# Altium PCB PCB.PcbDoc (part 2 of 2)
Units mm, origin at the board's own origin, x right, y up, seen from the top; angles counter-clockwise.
Board outline 85 x 56 mm, 4 copper layers (TOP, GND, SIG, BOTTOM), stack 1.586 mm thick; 75 components, 165 nets, 429 pads, 246 vias.

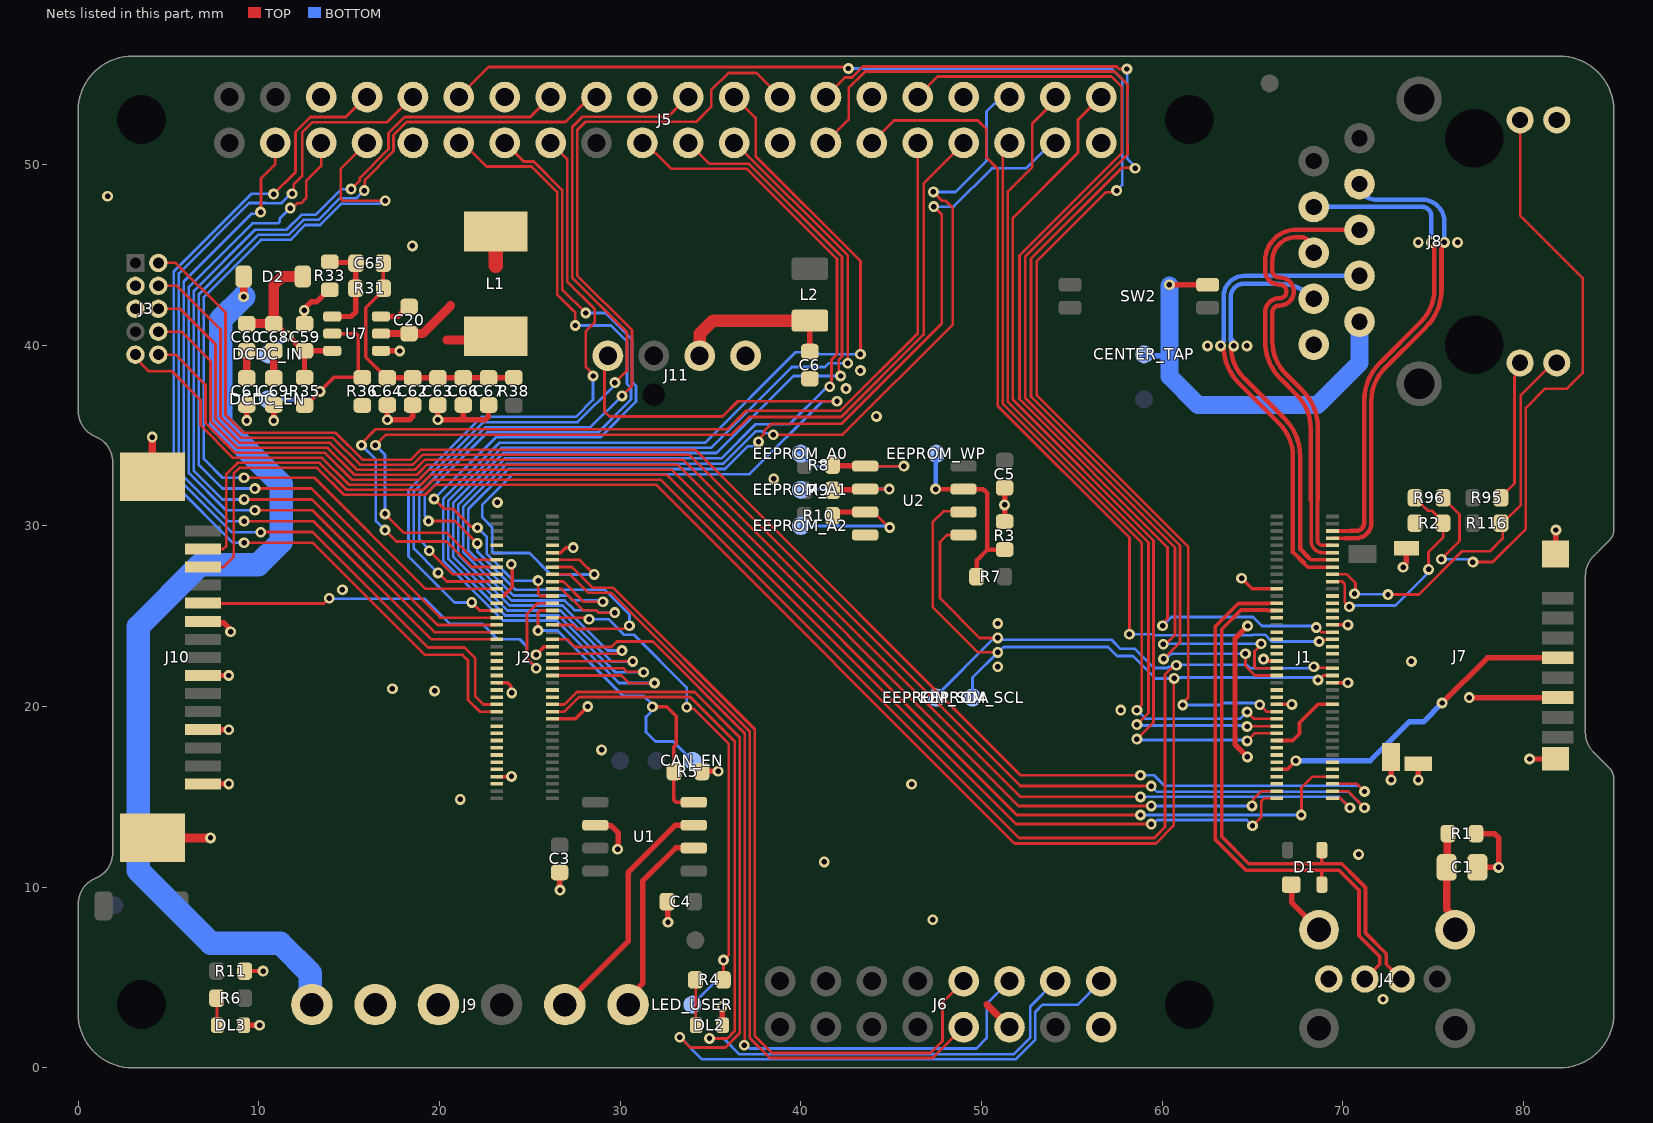
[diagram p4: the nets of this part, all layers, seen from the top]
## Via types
v1: diameter 0.6, hole 0.3, TOP to BOTTOM, tented both sides, 246 vias

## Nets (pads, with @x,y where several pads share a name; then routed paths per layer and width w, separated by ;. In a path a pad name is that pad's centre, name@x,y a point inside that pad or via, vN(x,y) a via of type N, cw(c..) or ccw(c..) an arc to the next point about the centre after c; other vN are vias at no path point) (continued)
ETH_B_N: J1.7 J8.8 | length 26.6
  TOP w0.2: J1.7@69.433,29.32 70.139,29.32 70.14,29.319
  TOP w0.25: 70.14,29.319 70.719,29.319 ccw(c70.719,30.187) 71.587,30.187 71.587,36.935 cw(c74.127,36.935) 72.331,38.731 74.603,41.003 ccw(c72.523,43.081) 75.463,43.063 75.463,45.322 cw(c75.743,45.322) 75.545,45.52 v1@75.56,45.534 ; v1@75.56,45.535 ccw(c75.398,45.696) v1(75.627,45.696)
  BOTTOM w0.25: J8.8@70.925,48.925 ccw(c71.79,48.925) 71.79,48.06 74.394,48.06 cw(c74.394,46.827) 75.627,46.827 v1(75.627,45.696)
ETH_B_P: J1.5 J8.7 | length 27.2
  TOP w0.2: J1.5@69.433,29.72 70.43,29.72
  TOP w0.25: 70.43,29.719 70.719,29.719 ccw(c70.719,30.187) 71.187,30.187 71.187,36.935 cw(c74.127,36.935) 72.048,39.014 74.32,41.285 ccw(c72.523,43.081) 75.063,43.065 75.063,45.322 ccw(c74.784,45.322) 74.982,45.52 v1@74.967,45.534 ; v1(74.9,45.696) ccw(c75.129,45.696) v1@74.967,45.535
  BOTTOM w0.25: J8.7@68.385,47.655 68.385,47.66 74.394,47.66 cw(c74.394,47.154) 74.9,47.154 v1(74.9,45.696)
ETH_C_N: J1.11 J8.6 | length 25.5
  TOP w0.2: 68.222,31.425 68.247,31.4 68.247,29.168 ccw(c68.894,29.168) 68.894,28.52 J1.11@69.433,28.52
  TOP w0.25: 68.222,31.425 68.222,35.426 ccw(c65.682,35.426) 67.478,37.222 66.56,38.14 cw(c68.637,40.217) 65.7,40.217 65.7,40.677 65.7,41.821 cw(c66.479,41.821) 66.479,42.6 66.504,42.6 ccw(c66.504,42.979) 66.504,43.358 66.479,43.358 cw(c66.479,44.137) 65.7,44.137 65.7,44.462 65.7,44.672 cw(c67.415,44.676) 67.536,46.387 67.55,46.386 ccw(c67.568,46.635) 67.567,46.385 J8.6@70.925,46.385
ETH_C_P: J1.9 J8.5 | length 22.2
  TOP w0.2: 68.622,31.425 68.597,31.4 68.597,29.218 ccw(c68.894,29.218) 68.894,28.92 J1.9@69.433,28.92
  TOP w0.25: J8.5@68.385,45.115 ccw(c67.448,45.115) 67.851,45.961 ccw(c67.744,45.735) 67.745,45.985 67.565,45.985 cw(c67.568,46.635) 67.519,45.987 ccw(c67.415,44.676) 66.1,44.675 66.1,44.462 66.1,44.137 ccw(c66.479,44.137) 66.479,43.758 66.504,43.758 cw(c66.504,42.979) 66.504,42.2 66.479,42.2 ccw(c66.479,41.821) 66.1,41.821 66.1,40.677 66.1,40.218 ccw(c68.64,40.218) 66.844,38.422 67.763,37.503 cw(c65.689,35.429) 68.622,35.429 68.622,31.425
ETH_D_N: J1.15 J8.4 | length 26.4
  TOP w0.2: 67.857,27.936 68.073,27.72 J1.15@69.433,27.72
  TOP w0.25: v1@63.4,39.961 ccw(c66.337,39.961) 64.26,37.884 66.496,35.648 cw(c64.7,33.852) 67.24,33.852 67.24,28.553 67.857,27.936
  BOTTOM w0.25: v1@63.4,39.962 v1(63.237,39.962) 63.237,40.057 63.4,40.22 63.4,42.7 cw(c64.545,42.7) 64.545,43.845 J8.4@70.925,43.845
ETH_D_P: J1.13 J8.3 | length 23.1
  TOP w0.2: 68.14,28.219 68.239,28.12 J1.13@69.433,28.12
  TOP w0.25: v1@63.8,39.962 ccw(c66.34,39.962) 64.544,38.166 66.781,35.929 cw(c64.708,33.855) 67.64,33.855 67.64,28.719 68.14,28.219
  BOTTOM w0.25: J8.3@68.385,42.575 68.304,42.656 ccw(c66.508,40.86) 66.508,43.4 64.5,43.4 ccw(c64.5,42.7) 63.8,42.7 63.8,40.362 ; 63.8,40.362 63.8,40.22 v1@63.897,40.124 ; 63.8,40.362 63.897,40.266 v1@63.897,40.124 ; v1@63.897,40.124 63.897,40.029 v1(63.964,39.962) 63.964,40.057 v1@63.897,40.124
ETH_LED1: J1.17 J8.14 R116.1 | length 22.7
  TOP w0.15: J1.17@69.433,27.32 70.222,27.32 70.699,26.844 70.699,26.295 v1(70.648,26.244) ; v1(72.5,26.2) 74.206,26.2 76.604,28.598 78.148,28.598 78.85,29.3 R116.1@78.85,30.15 ; R116.1@78.85,30.152 79.856,31.158 79.856,37.256 81.625,39.025 J8.14@81.845,39.025
  BOTTOM w0.15: v1(70.648,26.244) 70.67,26.222 72.478,26.222 v1(72.5,26.2)
ETH_LED2: J1.19 R2.1 R96.2 | length 12.5
  TOP w0.15: J1.19@69.433,26.92 69.98,26.92 70.1,26.8 70.1,25.792 v1(70.368,25.524) ; R96.2@74,31.55 74,31.548 74.393,31.155 74.395,31.155 74.709,30.841 74.934,30.841 75.55,30.225 R2.1@75.55,30.15 ; v1(74.746,27.595) 74.746,28.559 75.558,29.371 R2.1@75.558,30.142
  BOTTOM w0.15: v1(70.368,25.524) 70.442,25.598 72.908,25.598 74.605,27.295 74.605,27.332 74.746,27.474 v1(74.746,27.595)
GND: C1.1 C3.2 C4.2 C5.2 C6.1 C59.2 C61.1 C62.1 C63.1 C64.2 C66.1 C67.1 C69.1 DL2.C DL3.C J1.22 J1.31 J1.42 J1.47 J1.54 J2.24 J2.33 J2.44 J2.57 J2.70 J3.3 J3.5 J4.4 J5.6 J5.9 J5.14 J5.20 J5.25 J5.30 J5.34 J5.39 J6.15 J7.6 J7.CD2 J7.SH1 J7.SH2 J7.SH3 J7.SH4 J8.1 J8.12 J9.2 J9.3 J10.1 J10.4 J10.7 J10.10 J10.FIX J11.4 R1.1 R2.2 R3.1 R5.1 R11.1 R33.1 R36.2 U1.2 U2.4 U7.4 | length 72
  TOP w0.2: R11.1@9.212,5.36 v1(10.237,5.36) ; J2.33@23.173,21.32 23.772,21.32 23.943,21.149 23.943,20.815 v1(24,20.758) ; J2.57@23.173,26.12 23.544,26.12 24.023,26.599 24.023,27.82 v1(23.967,27.876) ; v1(25.344,22.871) 25.792,23.32 J2.44@26.253,23.32 ; J2.24@26.253,19.32 27.524,19.32 v1(28.208,20.005) ; J2.70@26.253,28.52 26.703,28.52 26.982,28.799 v1(27.4,28.799) ; v1(64.398,27.104) 64.981,26.52 J1.22@66.353,26.52 ; v1(65.612,22.625) 65.72,22.625 65.826,22.52 J1.42@66.353,22.52 ; J1.54@66.353,20.12 v1(67.179,20.12) ; J1.47@69.433,21.32 v1(70.279,21.32) ; J1.31@69.433,24.52 v1(70.279,24.52)
  TOP w0.3: J10.1@6.9,15.72 v1(8.334,15.72) ; J10.4@6.9,18.72 v1(8.334,18.72) ; J10.7@6.9,21.72 v1(8.334,21.72) ; J10.10@6.9,24.72 6.972,24.648 8.05,24.648 8.378,24.32 8.378,24.202 v1(8.436,24.145) ; DL3.C@9.162,2.36 v1(10.04,2.36) ; v1(9.328,35.83) C61.1@9.328,36.694 ; v1(10.828,35.83) C69.1@10.828,36.694 ; C59.2@12.528,41.194 12.522,41.2 12.522,41.926 v1(12.515,41.932) 12.573,41.99 12.573,42.079 12.896,42.402 13.186,42.402 13.853,43.069 R33.1@13.928,43.069 ; U7.4@16.762,39.694 16.767,39.689 17.792,39.689 v1(17.796,39.684) ; C64.2@17.112,36.694 v1(17.112,35.873) 18.331,35.873 18.512,36.054 C62.1@18.512,36.694 ; C63.1@19.912,36.694 v1(19.912,35.873) 21.321,35.873 ; C66.1@21.321,36.685 21.321,35.873 ; C67.1@22.712,36.694 22.712,36.054 22.531,35.873 21.321,35.873 ; C3.2@26.646,10.815 26.658,10.803 26.658,9.85 v1(26.67,9.838) ; U1.2@28.625,13.435 28.646,13.414 29.5,13.414 29.885,13.029 29.885,12.133 v1(29.857,12.104) ; C4.2@32.6,9.2 32.624,9.176 32.624,8.082 v1(32.649,8.057) ; R5.1@34.525,16.4 34.537,16.412 35.41,16.412 v1(35.422,16.423) ; v1(35.649,3.396) 35.656,3.389 35.656,2.367 DL2.C@35.662,2.36 ; R3.1@51.28,30.241 v1(51.28,31.166) C5.2@51.28,32.116 ; v1(64.722,17.215) 64.031,17.905 64.031,23.766 64.725,24.46 v1(64.728,24.46) ; v1(72.675,15.939) J7.CD2@72.675,17.197 ; v1(73.339,27.714) 73.339,27.795 73.502,27.957 73.502,28.751 J7.SH3@73.525,28.774 ; v1(74.175,15.939) J7.SH4@74.175,16.824 ; v1(77,20.5) J7.6@81.899,20.499 ; R1.1@77.371,12.965 78.396,12.965 78.495,12.866 78.621,12.74 v1(78.621,11.1) C1.1@77.45,11.101 ; v1(80.339,17.099) J7.SH1@81.772,17.099 ; J7.SH2@81.772,28.449 81.798,28.475 v1(81.798,29.774)
  TOP w0.4: J10.FIX@4.1,32.71 v1(4.1,34.918)
  TOP w0.5: J10.FIX@4.1,12.73 v1(7.322,12.73)
  other v1: 72.225,3.8 47.3,8.2 41.3,11.4 70.877,11.818 21.148,14.863 28.971,17.602 57.706,19.806 19.731,20.868 17.392,20.985 50.9,22.2 73.8,22.5 50.9,24.6 14.621,26.464 23.2,31.299 38.5,32.6 44.18,36.066 42.5,37.6 43.3,38.6 62.51,39.962 64.691,39.962 18.5,45.5 74.173,45.696 76.354,45.696 1.626,48.244
GPIO0_1: J2.46 J6.12 | length 47.7
  TOP w0.15: J2.46@26.253,23.72 27.08,23.72 27.503,23.297 29.508,23.297 29.812,23.601 31.81,23.601 36.896,18.515 36.896,7.371 36.896,1.278 v1(36.87,1.252)
  BOTTOM w0.15: v1(36.87,1.252) 36.992,1.252 37.166,1.078 49.717,1.078 50.287,1.648 50.287,3.537 J6.12@51.55,4.8
GPIO2_1: J2.50 J5.11 | length 54.6
  TOP w0.15: v1(19.389,30.269) 20.853,30.269 v1(22.088,29.034) ; J5.11@21.07,51.23 21.27,51.23 22.6,49.9 25.1,49.9 26.51,48.49 26.51,42.809 27.512,41.807 v1(27.512,41.094) ; J2.50@26.253,24.52 27.378,24.52 27.6,24.298 28.708,24.298 28.711,24.301 30.212,24.301 30.389,24.478 v1(30.511,24.478)
  BOTTOM w0.15: v1(19.389,30.269) 19.389,30.382 19.189,30.582 19.189,31.723 22.651,35.185 28.795,35.185 30.602,36.992 30.602,37.636 30.372,37.866 30.372,40.204 29.482,41.094 v1(27.512,41.094) ; v1(22.088,29.034) 22.088,28.574 24.193,26.469 29.141,26.469 30.511,25.099 v1(30.511,24.478)
GPIO02_SDA: J2.45 J5.3 | length 41.9
  TOP w0.15: v1(9.18,30.266) 13.009,30.266 19.554,23.72 J2.45@23.173,23.72 ; v1(10.094,47.367) 10.122,47.395 10.122,49.241 10.91,50.029 J5.3@10.91,51.23
  BOTTOM w0.15: v1(9.18,30.266) 8.29,30.266 5.844,32.712 5.844,43.544 9.581,47.281 10.008,47.281 v1(10.094,47.367)
GPIO3_1: J2.52 LED_USER.X R4.2 | length 29.6
  TOP w0.15: J2.52@26.253,24.92 28.198,24.92 v1(28.281,24.837) ; v1(33.682,19.959) 33.758,19.882 34.048,19.882 36.012,17.918 36.012,6.257 v1(35.719,5.964) R4.2@35.719,4.877
  BOTTOM w0.15: v1(28.281,24.837) 29.353,24.837 30.214,23.976 30.761,23.976 33.682,21.055 v1(33.682,19.959) ; LED_USER.X@34,3.501 35.719,5.22 v1(35.719,5.964)
GPIO03_SCL: J2.47 J5.5 | length 43.1
  TOP w0.15: v1(9.78,30.866) 12.974,30.866 19.72,24.12 J2.47@23.173,24.12 ; v1(11.737,47.594) 11.858,47.594 12.117,47.853 12.326,47.853 12.62,48.147 12.62,49.082 13.45,49.912 J5.5@13.45,51.23
  BOTTOM w0.15: v1(9.78,30.866) 8.18,30.866 6.121,32.925 6.121,43.228 9.64,46.748 11.057,46.748 11.156,46.847 11.156,47.013 v1(11.737,47.594)
GPIO4_1: CAN_EN.X J2.54 R5.2 U1.8 | length 22.2
  TOP w0.15: v1(25.452,24.208) 25.452,25.232 25.54,25.32 J2.54@26.253,25.32
  TOP w0.2: v1(31.786,19.993) 32.581,19.993 33.111,19.462 33.111,17.92 32.975,17.784 R5.2@32.975,16.4 32.975,14.825 33.095,14.705 U1.8@34.075,14.705
  BOTTOM w0.15: v1(25.452,24.208) 26.539,24.208 30.146,20.6 31.3,20.6 31.786,20.114 v1(31.786,19.993) 31.7,19.907 31.7,19.7 31.429,19.429 31.429,18.583 31.95,18.062 32.938,18.062 CAN_EN.X@34,17
GPIO04_1WIRE: J2.59 J5.7 | length 46.7
  TOP w0.15: v1(9.18,32.666) 13.08,32.666 19.225,26.52 J2.59@23.173,26.52 ; J5.7@15.99,51.23 14.537,49.777 14.537,48.105 14.643,48 v1(17,48)
  BOTTOM w0.15: v1(9.18,32.666) 7.98,32.666 6.952,33.694 6.952,42.677 10.11,45.835 11.745,45.835 12.565,46.654 13.391,46.654 14.576,47.839 16.717,47.839 16.878,48 v1(17,48)
GPIO05: J1.35 J5.29 | length 49.8
  TOP w0.15: J5.29@43.93,51.23 45.146,52.446 49.793,52.446 50.269,51.969 50.269,50.395 50.9,49.764 50.9,36.647 58.187,29.36 v1(58.187,24.004) ; v1(68.685,23.6) 68.807,23.6 68.901,23.695 69.408,23.695 J1.35@69.433,23.72
  BOTTOM w0.15: v1(58.187,24.004) 59.508,24.004 59.561,23.951 65.008,23.951 65.038,23.982 65.684,23.982 66.065,23.6 v1(68.685,23.6)
GPIO5_1: J2.56 J10.11 | length 25.5
  TOP w0.15: J10.11@6.9,25.72 6.91,25.711 13.611,25.711 v1(13.9,26) ; v1(25.353,22.125) 25.353,22.152 24.842,22.664 24.842,25.131 25.43,25.72 J2.56@26.253,25.72
  BOTTOM w0.15: v1(13.9,26) 13.938,25.962 19.183,25.962 20.58,24.566 22.38,24.566 23.22,23.726 24.44,23.726 24.83,23.336 24.83,22.648 v1(25.353,22.125)
GPIO06: J2.65 J5.31 | length 56.3
  TOP w0.15: v1(15.68,34.466) 15.68,34.566 16.469,35.355 35.951,35.355 36.977,36.381 42.191,36.381 46.47,40.66 J5.31@46.47,51.23 ; v1(16.98,29.766) 17.61,29.136 20.377,29.136 21.793,27.72 J2.65@23.173,27.72
  BOTTOM w0.15: v1(15.68,34.466) 16.478,33.668 16.478,30.268 v1(16.98,29.766)
GPIO6_1: J2.58 J5.13 | length 41.5
  TOP w0.15: v1(19.699,31.491) 20.241,30.949 20.751,30.949 21.729,29.971 22.029,29.971 v1(22.1,29.9) ; J5.13@23.61,51.23 24.663,50.177 25.215,50.177 26.787,48.605 26.787,43.094 v1(28.098,41.784) ; v1(25.457,26.971) 25.457,26.243 25.58,26.12 J2.58@26.253,26.12
  BOTTOM w0.15: v1(19.699,31.491) 23.116,34.908 28.91,34.908 30.879,36.877 30.879,37.751 30.649,37.981 30.649,40.319 29.184,41.784 v1(28.098,41.784) ; v1(22.1,29.9) 22.617,29.383 22.617,28.437 24.083,26.971 v1(25.457,26.971)
GPIO07_SPI0_CE1_N: J2.63 J5.26 | length 51
  TOP w0.15: v1(19.428,28.629) 20.737,27.32 J2.63@23.173,27.32 ; v1(30.1,37.2) 30.649,37.749 30.649,40.835 27.618,43.866 27.618,51.902 28.087,52.372 34.213,52.372 35.036,53.194 35.036,54.12 35.987,55.071 37.549,55.071 J5.26@38.85,53.77
  BOTTOM w0.15: v1(19.428,28.629) 19.428,28.704 18.883,29.249 18.883,31.81 22.542,35.468 28.368,35.468 v1(30.1,37.2)
GPIO08_SPI0_CE0_N: J2.36 J5.24 | length 67.4
  TOP w0.15: J2.36@26.253,21.72 30.079,21.72 30.5,21.299 31.893,21.299 v1(31.9,21.306) ; J5.24@36.31,53.77 37.5,52.58 37.5,50.461 43.3,44.661 v1(43.3,39.5)
  BOTTOM w0.15: v1(31.9,21.306) 29.927,21.306 28.767,22.466 28.748,22.466 27.967,23.247 27.967,23.266 26.469,24.764 23.525,24.764 20.201,28.087 20.201,31.283 20.201,31.495 23.306,34.6 34.7,34.6 39.718,39.618 40.892,39.618 41.008,39.502 43.298,39.502 v1(43.3,39.5)
GPIO09_SPI0_MISO: J2.40 J5.21 | length 62
  TOP w0.15: J2.40@26.253,22.52 26.263,22.51 30.689,22.51 v1(30.7,22.499) ; J5.21@33.77,51.23 34.955,50.045 37.133,50.045 42.277,44.9 42.277,39.387 42.098,39.208 42.098,38.613 42.114,38.597 42.114,38.386 v1(42.2,38.3)
  BOTTOM w0.15: v1(30.7,22.499) 29.518,22.499 28.997,23.02 28.977,23.02 28.521,23.476 28.521,23.496 26.699,25.318 23.754,25.318 20.755,28.317 20.755,31.053 20.755,31.266 23.528,34.038 35.328,34.038 39.59,38.3 v1(42.2,38.3)
GPIO10_SPI0_MOSI: J2.42 J5.19 | length 61.9
  TOP w0.15: J2.42@26.253,22.92 29.799,22.92 29.978,23.099 v1(30.1,23.099) ; J5.19@31.23,51.23 31.37,51.23 32.832,49.768 37.018,49.768 42,44.786 42,39.502 41.698,39.2 41.698,38.013 41.686,38.001 41.686,37.786 v1(41.6,37.7)
  BOTTOM w0.15: v1(30.1,23.099) 29.309,23.099 29.111,23.297 29.092,23.297 28.798,23.591 28.798,23.61 26.814,25.595 23.869,25.595 21.032,28.432 21.032,30.939 21.032,31.151 23.619,33.738 35.608,33.738 37.496,35.626 39.365,35.626 41.298,37.559 41.338,37.559 41.478,37.7 v1(41.6,37.7)
GPIO11_SPI0_SCLK: J2.38 J5.23 | length 61.9
  TOP w0.15: J2.38@26.253,22.12 30.179,22.12 30.378,21.921 31.278,21.921 v1(31.3,21.899) ; J5.23@36.31,51.23 36.339,51.23 42.6,44.969 v1(42.6,39)
  BOTTOM w0.15: v1(31.3,21.899) 29.726,21.899 28.882,22.743 28.863,22.743 28.244,23.362 28.244,23.381 26.584,25.041 23.639,25.041 20.478,28.202 20.478,31.168 20.478,31.38 23.421,34.323 35.023,34.323 39.5,38.8 39.99,38.8 39.992,38.802 41.339,38.802 41.537,39 v1(42.6,39)
GPIO12: J1.33 J5.32 | length 57.6
  TOP w0.15: J5.32@46.47,53.77 47.572,54.872 57.199,54.872 57.767,54.305 57.767,50.637 52.1,44.971 52.1,37.014 60.3,28.814 60.3,24.874 60.026,24.6 v1(60.026,24.478) ; v1(68.533,24.379) 68.545,24.379 68.804,24.12 J1.33@69.433,24.12
  BOTTOM w0.15: v1(60.026,24.478) 60.509,24.962 65.024,24.962 65.528,24.458 68.454,24.458 v1(68.533,24.379)
GPIO13: J2.67 J5.33 | length 55.6
  TOP w0.15: v1(16.453,34.466) 17.04,35.052 36.165,35.052 37.147,36.034 42.236,36.034 46.798,40.596 46.798,48.958 J5.33@49.01,51.17 ; v1(16.98,30.666) 18.026,29.62 20.426,29.62 21.925,28.12 J2.67@23.173,28.12
  BOTTOM w0.15: v1(16.453,34.466) 16.98,33.939 v1(16.98,30.666)
GPIO14_TX: J2.25 J5.8 | length 52.2
  TOP w0.15: v1(9.18,29.066) 13,29.066 19.2,22.866 21.28,22.866 21.58,22.566 21.58,20.366 22.225,19.72 J2.25@23.173,19.72 ; v1(10.813,48.368) 12.022,49.577 12.022,51.801 12.85,52.629 14.809,52.629 15.949,53.77 J5.8@15.99,53.77
  BOTTOM w0.15: v1(9.18,29.066) 8.58,29.066 5.29,32.356 5.29,44.092 9.585,48.387 10.794,48.387 v1(10.813,48.368)
GPIO15_RX: J2.27 J5.10 | length 54.1
  TOP w0.15: v1(10.107,29.652) 10.12,29.666 12.966,29.666 19.366,23.266 21.38,23.266 21.98,22.666 21.98,20.566 22.425,20.12 J2.27@23.173,20.12 ; v1(11.839,48.391) 11.926,48.477 11.926,48.899 12.398,49.371 12.398,51.786 12.96,52.348 17.107,52.348 J5.10@18.53,53.77
  BOTTOM w0.15: v1(10.107,29.652) 8.493,29.652 5.567,32.579 5.567,43.977 9.459,47.869 10.358,47.869 10.361,47.866 11.259,47.866 11.784,48.391 v1(11.839,48.391)
GPIO16: J2.60 J5.36 | length 63.6
  TOP w0.15: J2.60@26.253,26.52 26.756,26.52 27.937,25.339 28.659,25.339 28.798,25.2 v1(29.7,25.2) ; v1(38.471,35.051) 42.313,35.051 48.416,41.153 48.416,47.599 48.014,48 47.825,48 v1(47.337,48.487)
  BOTTOM w0.15: 21.309,30.824 21.309,28.546 23.984,25.872 26.928,25.872 27.461,25.339 28.671,25.339 28.81,25.2 v1(29.7,25.2) ; 21.309,30.824 21.309,31.036 23.711,33.438 35.7,33.438 37.495,35.233 37.871,35.233 37.967,35.137 38.385,35.137 v1(38.471,35.051) ; v1(47.337,48.487) 48.556,48.487 50.278,50.21 50.278,52.931 50.723,53.376 50.737,53.376 51.131,53.77 J5.36@51.55,53.77
GPIO18_PCM_CLK: J1.56 J5.12 | length 83.6
  TOP w0.15: J5.12@21.07,53.77 22.708,55.408 42.323,55.408 42.325,55.406 42.55,55.406 v1(42.636,55.32) ; v1(57.479,48.562) 57.392,48.476 56.886,48.476 53.067,44.657 53.067,37.223 61.452,28.837 61.452,20.515 61.138,20.201 v1(61.138,20.086) ; v1(65.4,20.1) 65.78,19.72 J1.56@66.353,19.72
  BOTTOM w0.15: v1(42.636,55.32) 57.193,55.32 57.786,54.728 57.786,48.869 v1(57.479,48.562) ; v1(61.138,20.086) 63.161,20.086 63.276,20.201 65.177,20.201 65.278,20.1 v1(65.4,20.1)
GPIO19: J1.58 J5.35 | length 43.1
  TOP w0.15: J5.35@51.55,51.23 51.55,50.811 51.184,50.444 51.184,36.755 58.876,29.063 58.876,20.112 58.6,19.836 v1(58.6,19.799) ; v1(64.7,19.699) 65.079,19.32 J1.58@66.353,19.32
  BOTTOM w0.15: v1(58.6,19.799) 59.069,19.33 64.331,19.33 v1(64.7,19.699)
GPIO20: J1.60 J5.38 | length 47.2
  TOP w0.15: J5.38@54.09,53.77 54.09,53.561 52.817,52.288 52.817,49.87 51.461,48.513 51.461,36.87 59.247,29.084 59.247,19.646 v1(58.6,18.999) ; v1(64.7,18.899) 64.711,18.91 66.342,18.91 J1.60@66.353,18.92
  BOTTOM w0.15: v1(58.6,18.999) 58.65,18.949 64.65,18.949 v1(64.7,18.899)
GPIO21: J1.62 J5.40 | length 49.2
  TOP w0.15: J5.40@56.63,53.77 55.342,52.482 55.342,50.655 51.738,47.051 51.738,36.985 59.524,29.198 59.524,19.123 v1(58.6,18.199) ; v1(64.7,18.099) 65.121,18.52 J1.62@66.353,18.52
  BOTTOM w0.15: v1(58.6,18.199) 58.65,18.149 64.65,18.149 v1(64.7,18.099)
GPIO22: J2.53 J5.15 | length 37.7
  TOP w0.15: v1(21.78,25.766) 22.225,25.32 J2.53@23.173,25.32 ; J5.15@26.15,51.23 27.064,50.316 27.064,43.527 28.6,41.992 28.6,41.281 28.1,40.782 28.1,38.798 28.5,38.398 v1(28.5,38.3)
  BOTTOM w0.15: v1(21.78,25.766) 20.834,25.766 18.282,28.318 18.282,31.992 22.33,36.039 27.548,36.039 28.5,36.992 v1(28.5,38.3)
GPIO23: J2.49 J5.16 | length 55.1
  TOP w0.15: v1(9.18,31.466) 12.94,31.466 19.886,24.52 J2.49@23.173,24.52 ; v1(15.107,48.643) 15.586,49.122 15.586,49.27 17.174,50.858 17.174,51.753 18.061,52.641 25.021,52.641 J5.16@26.15,53.77
  BOTTOM w0.15: v1(9.18,31.466) 7.98,31.466 6.398,33.048 6.398,43.013 9.774,46.389 11.516,46.389 12.348,47.221 13.144,47.221 14.565,48.643 v1(15.107,48.643)
GPIO24: J2.51 J5.18 | length 56.9
  TOP w0.15: v1(9.78,32.066) 12.906,32.066 20.051,24.92 J2.51@23.173,24.92 ; v1(15.829,48.56) 15.863,48.593 15.863,49.156 17.451,50.743 17.451,51.638 18.176,52.364 26.964,52.364 28.37,53.77 J5.18@28.69,53.77
  BOTTOM w0.15: v1(9.78,32.066) 7.98,32.066 6.675,33.371 6.675,42.825 9.962,46.112 11.631,46.112 12.463,46.944 13.289,46.944 14.486,48.141 15.41,48.141 v1(15.829,48.56)
GPIO25: J2.61 J5.22 | length 45
  TOP w0.15: v1(19.923,27.4) 20.403,26.92 J2.61@23.173,26.92 ; v1(29.709,37.93) 30.372,38.593 30.372,40.72 27.341,43.751 27.341,52.068 27.921,52.649 32.649,52.649 J5.22@33.77,53.77
  BOTTOM w0.15: v1(19.923,27.4) 18.578,28.745 18.578,31.896 22.427,35.745 27.645,35.745 29.709,37.809 v1(29.709,37.93)
GPIO26: J2.62 J5.37 | length 59.7
  TOP w0.15: J2.62@26.253,26.92 26.862,26.92 27.978,25.804 v1(29.043,25.804) ; v1(37.656,34.654) 37.656,34.77 37.969,35.083 37.969,35.259 38.366,35.656 42.249,35.656 47.8,41.207 47.8,47.232 v1(47.357,47.675)
  BOTTOM w0.15: v1(29.043,25.804) 28.961,25.886 27.363,25.886 27.1,26.149 24.098,26.149 21.586,28.661 21.586,30.709 21.586,30.922 23.812,33.147 35.8,33.147 37.057,34.404 37.375,34.404 37.625,34.654 v1(37.656,34.654) ; v1(47.357,47.675) 48.454,47.675 50.571,49.792 52.472,49.792 53.91,51.23 J5.37@54.09,51.23
I2C0.SCL_1: J1.46 J5.28 | length 64.2
  TOP w0.15: J5.28@41.39,53.77 42.438,54.818 42.844,54.818 43.451,55.426 57.48,55.426 57.615,55.29 v1(58.05,55.29) ; v1(58.5,49.8) 58.479,49.821 57.763,49.821 52.744,44.803 52.744,37.153 60.983,28.914 60.983,23.538 v1(60.083,22.638) ; v1(64.608,22.921) 64.608,22.249 65.137,21.72 J1.46@66.353,21.72
  BOTTOM w0.15: v1(58.05,55.29) 58.038,55.278 58.038,54.995 58.063,54.97 58.063,50.342 58.5,49.905 v1(58.5,49.8) ; v1(60.083,22.638) 60.205,22.638 60.488,22.921 v1(64.608,22.921)
I2C0.SDA_1: J1.44 J5.27 | length 64.9
  TOP w0.15: J5.27@41.39,51.23 42.65,52.49 42.65,54.233 43.566,55.149 57.365,55.149 58.08,54.434 58.08,53.923 58.075,53.918 58.075,51.08 58.08,51.075 58.08,50.559 52.422,44.901 52.422,37.084 60.706,28.799 60.706,23.972 60.183,23.449 v1(60.061,23.449) ; v1(65.476,23.48) 65.476,23.421 65.11,23.055 65.11,22.208 65.198,22.12 J1.44@66.353,22.12
  BOTTOM w0.15: v1(60.061,23.449) 60.084,23.471 65.468,23.471 v1(65.476,23.48)
I2C1.SCL_1: EEPROM_SCL.X J1.45 J10.13 U2.6 | length 110.3
  TOP w0.15: J10.13@6.9,27.72 8.034,27.72 8.559,28.244 ccw(c8.453,28.351) 8.603,28.351 8.603,32.895 8.924,33.217 13.215,33.217 14.705,31.726 19.214,31.726 19.771,32.282 31.977,32.282 51.833,12.426 59.654,12.426 60.636,13.409 60.636,21.53 v1(60.665,21.559) ; U2.6@49.012,30.769 48.977,30.804 47.887,30.804 47.298,30.215 47.298,25.502 49.8,23 v1(50.9,23) ; v1(68.627,21.472) 68.675,21.472 68.923,21.72 J1.45@69.433,21.72
  BOTTOM w0.15: EEPROM_SCL.X@49.5,20.5 49.5,21.6 v1(50.9,23) ; v1@50.913,23 51.213,23.3 57,23.3 57.5,22.8 58.391,22.8 59.632,21.559 v1(60.665,21.559) 60.712,21.606 68.371,21.606 68.506,21.472 v1(68.627,21.472)
I2C1.SDA_1: EEPROM_SDA.X J1.43 J10.14 U2.5 | length 109.1
  TOP w0.15: J10.14@6.9,28.72 8.02,28.72 8.2,28.9 8.2,32.884 8.809,33.494 13.359,33.494 14.85,32.003 19.099,32.003 19.656,32.559 32.241,32.559 52.074,12.726 59.562,12.726 60.163,13.327 60.163,21.767 60.685,22.289 v1(60.786,22.289) ; U2.5@49.012,29.499 48.082,29.499 47.698,29.115 47.698,26.002 49.9,23.8 v1(50.9,23.8) ; v1(68.403,22.2) 68.458,22.145 69.408,22.145 J1.43@69.433,22.12
  BOTTOM w0.15: EEPROM_SDA.X@47.5,20.5 47.5,20.6 50.614,23.714 50.814,23.714 v1(50.9,23.8) 50.986,23.714 51.199,23.714 51.213,23.7 57.2,23.7 57.702,23.198 58.493,23.198 59.555,22.136 60.291,22.136 60.358,22.202 60.7,22.202 v1(60.786,22.289) 60.817,22.32 64.67,22.32 64.869,22.12 68.322,22.12 v1(68.403,22.2)
JTAG_RST_1: J1.73 J3.10 | length 79
  TOP w0.15: J3.10@4.435,39.48 5.376,39.48 7.046,37.81 7.046,35.695 8.694,34.048 13.653,34.048 15.144,32.557 18.87,32.557 19.426,33.113 32.839,33.113 51.953,13.999 58.798,13.999 v1(58.8,13.997) ; v1(67.7,13.999) 67.712,14.011 67.712,15.511 68.321,16.12 J1.73@69.433,16.12
  BOTTOM w0.15: v1(58.8,13.997) 58.802,13.999 v1(67.7,13.999)
JTAG_SCK_1: J1.77 J3.4 | length 84.2
  TOP w0.15: J3.4@4.435,43.29 5.466,43.29 7.877,40.879 7.877,36.039 9.038,34.879 14.095,34.879 15.586,33.388 18.525,33.388 19.082,33.944 33.808,33.944 52.153,15.599 v1(59.4,15.599) ; J1.77@69.433,15.32 70.28,15.32 v1(71.2,14.4)
  BOTTOM w0.15: v1(59.4,15.599) 59.719,15.28 70.32,15.28 v1(71.2,14.4)
JTAG_SWD_1: J1.75 J3.2 | length 84.6
  TOP w0.15: J3.2@4.435,44.56 5.396,44.56 8.154,41.802 8.154,36.154 9.153,35.156 14.243,35.156 15.733,33.665 18.411,33.665 18.967,34.221 34.131,34.221 52.153,16.199 v1(58.8,16.199) ; J1.75@69.433,15.72 70.78,15.72 v1(71.2,15.3)
  BOTTOM w0.15: v1(58.8,16.199) 59.54,16.199 60.116,15.623 70.877,15.623 v1(71.2,15.3)
JTAG_SWO_1: J1.79 J3.6 | length 81.5
  TOP w0.15: J3.6@4.435,42.02 5.636,42.02 7.6,40.056 7.6,35.925 8.923,34.602 13.948,34.602 15.439,33.111 18.64,33.111 19.197,33.667 33.485,33.667 52.149,15.003 v1(58.8,15.003) ; J1.79@69.433,14.92 69.88,14.92 v1(70.4,14.4)
  BOTTOM w0.15: v1(58.8,15.003) 61.704,15.003 ; 61.704,15.003 69.797,15.003 v1(70.4,14.4)
JTAG_TDI_1: J1.78 J3.8 | length 75.7
  TOP w0.15: J3.8@4.435,40.75 5.706,40.75 7.323,39.133 7.323,35.81 8.809,34.325 13.801,34.325 15.292,32.834 18.755,32.834 19.312,33.39 33.162,33.39 52.051,14.501 v1(59.4,14.501) ; v1(64.976,14.501) 65.046,14.572 65.046,14.873 65.493,15.32 J1.78@66.353,15.32
  BOTTOM w0.15: v1(59.4,14.501) v1@64.884,14.501 ; v1@64.884,14.501 v1(64.976,14.501)
JTAG_TRST_1: J1.80 J3.9 | length 76.7
  TOP w0.15: J3.9@3.165,39.48 3.165,39.296 3.895,38.565 5.178,38.565 6.769,36.974 6.769,35.58 8.579,33.771 13.506,33.771 14.997,32.28 18.984,32.28 19.541,32.836 32.564,32.836 51.905,13.495 59.008,13.495 59.01,13.497 v1(59.4,13.497) ; v1(65,13.399) 65.493,13.892 65.493,14.763 65.65,14.92 J1.80@66.353,14.92
  BOTTOM w0.15: v1(59.4,13.497) 59.488,13.497 59.713,13.722 64.677,13.722 v1(65,13.399)
LICELL_1: J2.7 J6.11 | length 2.6
  TOP w0.2: J2.7@23.173,16.12 23.971,16.12 v1(23.986,16.135)
  TOP w0.4: 50.309,3.501 J6.11@51.55,2.26
  other v1: 46.131,15.699
NetC1_2: C1.2 J4.5 R1.2 | length 5.5
  TOP w0.4: R1.2@75.821,12.965 75.785,12.93 75.785,11.136 C1.2@75.75,11.101 75.75,8.774 75.87,8.654 75.87,7.985 J4.5@76.215,7.64
NetC6_2: C6.2 J11.3 L2.2 | length 9.4
  TOP w0.3: C6.2@40.5,39.65 L2.2@40.5,41.365
  TOP w0.7: J11.3@34.4,39.358 34.4,40.621 35.144,41.365 L2.2@40.5,41.365
NetC20_1: C20.1 U7.6 | length 1.8
  TOP w0.3: U7.6@16.762,41.594 17.712,41.594 18.262,42.144 C20.1@18.312,42.144
NetC20_2: C20.2 L1.1 U7.5 | length 6.2
  TOP w0.4: U7.5@16.762,40.644 C20.2@18.094,40.644
  TOP w0.5: C20.2@18.312,40.644 19.062,40.644 20.612,42.194
  TOP w0.8: 23.112,44.394 L1.1@23.112,46.294
NetC59_1: C59.1 C60.2 C68.2 D2.C DCDC_IN.X R35.1 U7.3 | length 12.2
  TOP w0.3: C68.2@10.878,41.194 10.909,41.194 11.581,40.521 11.631,40.521 12.459,39.694 C59.1@12.528,39.694 ; R35.1@12.528,38.219 C59.1@12.528,39.694 ; U7.3@14.062,39.694 C59.1@12.528,39.694
  TOP w0.5: C60.2@9.328,41.194 C68.2@10.728,41.194
  TOP w0.6: C68.2@10.828,41.194 10.828,43.333 11.301,43.806 D2.C@12.428,43.806
  BOTTOM w0.3: DCDC_IN.X@10.5,39.5 10.545,39.5 11.566,40.521 v1(11.612,40.521)
NetC60_1: C60.1 C61.2 | length 1.5
  TOP w0.4: C61.2@9.328,38.194 C60.1@9.328,39.694
NetC62_2: C62.2 C63.2 C64.1 C65.2 C66.2 C67.2 L1.2 R31.1 R38.1 | length 16.9
  TOP w0.2: C65.2@16.878,44.544 16.878,43.044 15.912,42.078 15.912,39.345 17.062,38.194 C64.1@17.112,38.194
  TOP w0.3: C64.1@17.112,38.194 17.125,38.207 19.912,38.207 24.1,38.207 R38.1@24.112,38.219
  TOP w0.5: 20.412,40.294 22.712,40.294 L1.2@22.912,40.494
  TOP w0.6: C63.2@19.912,38.194 C63.2@19.912,38.207
NetC65_1: C65.1 R31.2 R33.2 U7.1 | length 5.7
  TOP w0.3: R33.2@13.928,44.619 13.965,44.581 15.34,44.581 C65.1@15.378,44.544 15.365,44.531 15.365,41.851 15.108,41.594 U7.1@14.062,41.594 U7.1@14.008,41.649
NetC68_1: C68.1 C69.2 | length 1.5
  TOP w0.4: C69.2@10.828,38.194 C68.1@10.828,39.694
NetCENTER_TAP_X: CENTER_TAP.X J8.2 SW2.2 | length 23
  TOP w0.3: v1(60.4,43.351) SW2.2@62.52,43.351
  BOTTOM w0.3: CENTER_TAP.X@59,39.42 60.4,39.42
  BOTTOM w1: v1@60.4,43.3 60.4,39.42 60.4,38.284 61.984,36.7 68.6,36.7 70.925,39.025 J8.2@70.925,41.305
NetD1_1: D1.1 J4.6 | length 3.1
  TOP w0.3: D1.1@67.143,10.146 67.166,10.123 67.166,9.159 J4.6@68.685,7.64
NetD2_A: D2.A J9.1 | length 53.6
  TOP w0.4: v1(9.158,42.687) D2.A@9.158,43.806
  BOTTOM w1.3: v1(9.158,42.687) 7.894,41.422 7.894,35.648 8.251,35.29 8.251,35.283 8.882,34.653 8.889,34.653 11.237,32.305 11.237,29.13 9.957,27.85 6.744,27.85 3.318,24.424 3.318,10.928 7.344,6.902 11.178,6.902 12.854,5.226 12.854,3.584 J9.1@12.937,3.501
NetDCDC_EN_X: DCDC_EN.X R35.2 R36.1 U7.2 | length 10.8
  TOP w0.2: R35.2@12.528,36.669 12.603,36.669 v1(13.378,37.444) 14.153,38.219 R36.1@15.728,38.219 15.512,38.435 15.512,40.527 15.395,40.644 U7.2@14.062,40.644
  BOTTOM w0.2: DCDC_EN.X@10.5,37 12.934,37 v1(13.378,37.444)
NetDL2_A: DL2.A R4.1 | length 2.5
  TOP w0.15: R4.1@34.162,4.87 34.187,4.845 34.187,2.385 DL2.A@34.212,2.36
NetDL3_A: DL3.A R6.1 | length 1.5
  TOP w0.15: R6.1@7.662,3.86 7.687,3.835 7.687,2.385 DL3.A@7.712,2.36
NetEEPROM_A0_X: EEPROM_A0.X R8.1 U2.1 | length 10.2
  TOP w0.15: U2.1@43.562,33.309 U2.1@43.562,33.309 v1(45.708,33.311) v1(45.708,33.311)
  TOP w0.3: R8.1@41.755,33.366 41.783,33.337 43.534,33.337 U2.1@43.562,33.309
  BOTTOM w0.15: EEPROM_A0.X@39.837,34.163 40.691,33.309 v1(45.708,33.311) v1(45.708,33.311)
NetEEPROM_A1_X: EEPROM_A1.X R9.1 U2.2 | length 8.1
  TOP w0.15: U2.2@43.562,32.039 v1(44.891,32.039)
  TOP w0.3: R9.1@41.755,31.966 41.792,32.002 43.525,32.002 U2.2@43.562,32.039
  BOTTOM w0.15: EEPROM_A1.X@40,31.875 40.375,31.875 40.539,32.039 v1(44.891,32.039)
NetEEPROM_A2_X: EEPROM_A2.X R10.1 U2.3 | length 8.6
  TOP w0.15: U2.3@43.562,30.769 44.027,30.769 44.882,29.915 v1(44.922,29.915)
  TOP w0.3: R10.1@41.755,30.566 41.958,30.769 U2.3@43.562,30.769
  BOTTOM w0.15: EEPROM_A2.X@40,30 44.837,30 v1(44.922,29.915)
NetEEPROM_WP_X: EEPROM_WP.X R3.2 R7.1 U2.7 | length 10.8
  TOP w0.25: v1(47.461,32.039) U2.7@49.012,32.039 50.107,32.039 50.331,31.815 50.331,28.691 ; R7.1@49.73,27.191 49.73,28.09 50.331,28.691 ; R3.2@51.28,28.691 50.331,28.691
  BOTTOM w0.25: v1(47.461,32.039) 47.461,33.961 EEPROM_WP.X@47.5,34
NetJ1_23: J1.23
NetJ1_29: J1.29
NetJ1_30: J1.30
NetJ1_34: J1.34
NetJ1_36: J1.36
NetJ1_38: J1.38
NetJ1_40: J1.40
NetJ1_50: J1.50
NetJ1_52: J1.52
NetJ1_66: J1.66
NetJ1_68: J1.68
NetJ1_69: J1.69
NetJ1_70: J1.70
NetJ1_71: J1.71
NetJ1_74: J1.74
NetJ1_76: J1.76
NetJ2_5: J2.5
NetJ2_21: J2.21
NetJ2_35: J2.35
NetJ2_37: J2.37
NetJ2_39: J2.39
NetJ2_41: J2.41
NetJ2_71: J2.71
NetJ2_72: J2.72
NetJ8_11: J8.11 R96.1 | length 35.8
  TOP w0.15: v1(75.455,28.159) 76.456,29.16 76.456,30.641 75.55,31.548 R96.1@75.55,31.55 ; v1(77.2,28) 78.3,28 80.133,29.833 80.133,36.533 81.2,37.6 82.406,37.6 83.275,38.469 83.275,43.725 79.815,47.185 J8.11@79.815,52.475
  BOTTOM w0.15: v1(75.455,28.159) 76.919,28.159 77.078,28 v1(77.2,28)
NetJ8_13: J8.13 R95.1 | length 7.7
  TOP w0.15: R95.1@78.85,31.698 79.5,32.348 79.5,38.262 79.557,38.319 79.557,38.767 J8.13@79.815,39.025
NetJ9_5: J9.5 U1.7 | length 13.5
  TOP w0.3: J9.5@26.937,3.501 30.443,7.007 30.443,10.812 33.066,13.435 U1.7@34.075,13.435
NetJ9_6: J9.6 U1.6 | length 10.8
  TOP w0.3: J9.6@30.437,3.501 30.437,3.869 31.245,4.677 31.245,10.349 33.081,12.185 34.055,12.185 U1.6@34.075,12.165
PCIE_CK_N: J2.19
PCIE_CK_P: J2.17
PCIE_RX_N: J2.15
PCIE_RX_P: J2.13
PCIE_TX_N: J2.11
PCIE_TX_P: J2.9
PWM7_1: J2.64 J6.9 | length 44.5
  TOP w0.15: J2.64@26.253,27.32 27.211,27.32 28.225,26.306 29.497,26.306 37.173,18.63 37.173,7.256 37.173,1.659 38.285,0.547 47.297,0.547 J6.9@49.01,2.26
PWM8_1: J2.66 J6.10 | length 46.7
  TOP w0.15: J2.66@26.253,27.72 27.327,27.72 28.465,26.583 29.612,26.583 37.45,18.744 37.45,7.141 37.45,1.774 38.4,0.824 47.182,0.824 47.837,1.479 47.837,3.627 J6.10@49.01,4.8
PWM9_1: J2.68 J11.1 | length 50.3
  TOP w0.15: J2.68@26.253,28.12 27.759,28.12 v1(28.566,27.313) ; J11.1@29.441,39.541 29.133,39.233 29.133,36.334 29.412,36.055 35.664,36.055 36.509,36.9 v1(42,36.9)
  BOTTOM w0.15: v1(28.566,27.313) 26.157,27.313 24.97,28.5 23.008,28.5 22.92,28.588 22.92,29.921 22.368,30.473 22.368,31.177 23.451,32.26 24.057,32.866 37.161,32.866 41.195,36.9 v1(42,36.9)
SAI.D1_1: J2.55
SERIAL1.CTS_1: J1.39
SERIAL1.RTS_1: J1.37
SERIAL2.CTS_1: J2.32
SERIAL2.RTS_1: J2.30
SERIAL2.RX_1: J2.28 J6.16 | length 58.5
  TOP w0.15: J2.28@26.253,20.12 26.92,20.12 27.604,20.804 34.103,20.804 36.619,18.289 36.619,1.927 35.822,1.13 33.87,1.13 v1(33.3,1.7)
  BOTTOM w0.15: v1(33.3,1.7) 34.527,0.473 51.886,0.473 52.979,1.566 52.979,3.107 53.373,3.501 55.331,3.501 J6.16@56.63,4.8
SERIAL2.TX_1: J2.26 J6.14 | length 51.2
  TOP w0.15: J2.26@26.253,19.72 26.912,19.72 27.719,20.527 33.88,20.527 36.342,18.066 36.342,2.042 35.932,1.632 v1(34.943,1.632)
  BOTTOM w0.15: v1(34.943,1.632) 35.733,1.632 36.615,0.75 51.772,0.75 52.702,1.68 52.702,3.412 J6.14@54.09,4.8
SERIAL3.CTS_1: J2.31
SERIAL3.RTS_1: J2.29
USB0_D_N: D1.3 J1.28 J4.2 | length 30.7
  TOP w0.2: 65.84,25.323 65.842,25.32 J1.28@66.353,25.32
  TOP w0.21: 65.84,25.323 65.823,25.34 64.361,25.34 63.3,24.279 63.3,12.799 64.796,11.303 68.84,11.303 ; D1.3@68.843,12.056 68.84,12.053 68.84,11.303 ; J4.2@73.225,4.92 72.407,5.738 72.405,5.738 72.405,6.32 71.258,7.466 71.258,9.984 71.153,10.089 70.752,10.49 69.939,11.303 68.84,11.303
USB0_D_P: D1.2 J1.26 J4.3 | length 31.4
  TOP w0.2: 65.857,25.7 65.877,25.72 J1.26@66.353,25.72
  TOP w0.21: 65.857,25.7 64.212,25.7 62.94,24.428 62.94,12.65 64.647,10.943 68.84,10.943 ; D1.2@68.843,10.146 68.84,10.149 68.84,10.943 ; J4.3@71.225,4.92 72.043,5.738 72.045,5.738 72.045,6.171 70.898,7.317 70.898,9.834 69.79,10.943 68.84,10.943
USB1_D_N: J1.27
USB1_D_P: J1.25
VDD_SDCARD: J1.72 J7.4 | length 18.1
  TOP w0.2: J1.72@66.353,16.52 66.923,16.52 v1(67.403,17.001)
  TOP w0.3: v1(75.5,20.2) 77.999,22.699 J7.4@81.9,22.699
  BOTTOM w0.3: v1(67.403,17.001) 71.513,17.001 73.669,19.157 74.457,19.157 v1(75.5,20.2)
VSYS: J1.53 J1.64 | length 4.3
  TOP w0.2: J1.64@66.353,18.12 67.221,18.12 67.6,18.499 67.6,19.099 68.621,20.12 J1.53@69.433,20.12
pads on no net: Fiducial_1.1 Fiducial_2.1 J3.7 J4.7 J4.8 J8.NC J8.NC1 J8.SH1 J8.SH2 J10.12 J11.2 J11.NC

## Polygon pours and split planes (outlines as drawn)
GND on TOP "c" (solid, remove dead copper, pour order 15): 0,3 ccw(c3,3) 3,0 82,0 ccw(c82,3) 85,3 85,16.019 ccw(c83.467,16.019) 84.551,17.103 84.179,17.475 cw(c85.263,18.559) 83.73,18.559 83.73,27.239 cw(c85.263,27.239) 84.179,28.323 84.551,28.695 ccw(c83.467,29.779) 85,29.779 85,53 ccw(c82,53) 82,56 3,56 ccw(c3,53) 0,53 0,36.363 ccw(c1.533,36.363) 0.959,34.941 cw(c0.384,33.52) 1.917,33.52 1.917,11.92 cw(c0.384,11.92) 0.959,10.499 ccw(c1.533,9.077) 0,9.077
+5V on TOP "+5V_L01_P011" (solid, remove dead copper, pour order 11): 12.226,55.706 12.226,47.044 16.512,47.044 16.512,49.378 25.622,49.378 27.212,47.511 27.212,36.044 24.612,36.044 24.612,38.494 24.971,39.009 24.971,44.914 23.826,45.644 18.026,45.644 17.626,45.389 8.26,45.389 6.847,46.801 6.847,55.706
NetC20_2 on TOP "NETC20_2_L01_P004" (solid, remove dead copper, pour order 4): 23.497,47.094 23.497,42.979 22.812,42.294 21.262,42.294 20.362,41.394 18.112,41.394 18.112,42.474 20.58,44.942 21.212,44.942 21.212,45.574 21.212,47.094
NetC62_2 on TOP "NETC62_2_L01_P003" (solid, remove dead copper, pour order 3): 20.912,41.151 20.912,37.93 18.312,37.93 18.312,39.194 20.27,41.151
+3V3_PORTENTA on TOP "+3V3_PORTENTA_L01_P010" (solid, remove dead copper, pour order 10): 4.741,45.444 7.767,42.044 7.767,29.43 5.3,29.43 5.3,15.1 8.7,15.1 12.983,10.817 19.817,10.817 23.3,14.3 25.9,14.3 25.9,12.4 21.8,8.3 8.7,8.3 6.395,10.605 6.395,14.205 6.2,14.4 3.4,14.4 0,17.8 0,45.444
+5V on TOP "+5V_L01_P009" (solid, remove dead copper, pour order 9): 28.7,46.2 40.1,46.2 40.9,45.4 40.9,43.5 36.5,43.5 35.2,44.8 28.7,44.8
LICELL_1 on TOP "LICELL_1_L01_P007" (solid, remove dead copper, pour order 7): 46.8,16 46.8,11.8 51.1,7.5 51.1,3.4 51.9,2.6 51.9,2 49.7,2 49.7,7.8 45.6,11.9 45.6,16
+3V3_PORTENTA on TOP "+3V3_PORTENTA_L01_P008" (solid, remove dead copper, pour order 8): 47.1,12.9 48.6,12.9 54.09,7.41 54.09,2.26 51.55,2.26 51.55,7.35 47.1,11.8
+3V3_PORTENTA on TOP "+3V3_PORTENTA_L01_P014" (solid, remove dead copper, pour order 14): 22.8,29.3 26.5,29.3 26.5,19.012 22.8,19.012 22.8,23.3
+5V on TOP "+5V_L01_P012" (solid, remove dead copper, pour order 12): 65.8,26.8 65.8,20.92 70.1,20.92 70.1,26.8
GND on BOTTOM "GND_L04_P013" (solid, remove dead copper, pour order 13): 0,3 ccw(c3,3) 3,0 82,0 ccw(c82,3) 85,3 85,16.019 ccw(c83.467,16.019) 84.551,17.103 84.179,17.475 cw(c85.263,18.559) 83.73,18.559 83.73,27.239 cw(c85.263,27.239) 84.179,28.323 84.551,28.695 ccw(c83.467,29.779) 85,29.779 85,53 ccw(c82,53) 82,56 3,56 ccw(c3,53) 0,53 0,36.363 ccw(c1.533,36.363) 0.959,34.941 cw(c0.384,33.52) 1.917,33.52 1.917,11.92 cw(c0.384,11.92) 0.959,10.499 ccw(c1.533,9.077) 0,9.077
LICELL_1 on BOTTOM "LICELL_1_L04_P001" (solid, remove dead copper, pour order 1): 23.445,16.488 24.712,16.488 25,16.2 46.9,16.2 46.9,15 28.6,15 28,15.6 23.709,15.6 23.445,15.865
GND on GND "GND_L02_P005" (solid, remove dead copper, pour order 5): 0,3 ccw(c3,3) 3,0 82,0 ccw(c82,3) 85,3 85,16.019 ccw(c83.467,16.019) 84.551,17.103 84.179,17.475 cw(c85.263,18.559) 83.73,18.559 83.73,27.239 cw(c85.263,27.239) 84.179,28.323 84.551,28.695 ccw(c83.467,29.779) 85,29.779 85,53 ccw(c82,53) 82,56 3,56 ccw(c3,53) 0,53 0,36.363 ccw(c1.533,36.363) 0.959,34.941 cw(c0.384,33.52) 1.917,33.52 1.917,11.92 cw(c0.384,11.92) 0.959,10.499 ccw(c1.533,9.077) 0,9.077
GND on SIG "GND_L03_P006" (solid, remove dead copper, pour order 6): 0,3 ccw(c3,3) 3,0 82,0 ccw(c82,3) 85,3 85,16.019 ccw(c83.467,16.019) 84.551,17.103 84.179,17.475 cw(c85.263,18.559) 83.73,18.559 83.73,27.239 cw(c85.263,27.239) 84.179,28.323 84.551,28.695 ccw(c83.467,29.779) 85,29.779 85,53 ccw(c82,53) 82,56 3,56 ccw(c3,53) 0,53 0,36.363 ccw(c1.533,36.363) 0.959,34.941 cw(c0.384,33.52) 1.917,33.52 1.917,11.92 cw(c0.384,11.92) 0.959,10.499 ccw(c1.533,9.077) 0,9.077

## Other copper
TOP:
  text ".VERSION" at 57.837,7.92 h1

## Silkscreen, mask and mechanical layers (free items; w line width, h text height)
Route Tool Path:
  lines w2: -1,5 -1,3 ; -1,9 -1,9.2 ; -1,47 -1,36.363 ; -1,51 -1,53 ; 86,5 86,3 ; 86,9 86,16.019 ; 86,36.363 86,47 ; 86,51 86,53 ; -1,3 ccw(c3,3) 3,-1 ; -1,3 ccw(c3,3) 3,-1 ; -1,3 -1,3 ; -1,9.077 cw(c1.533,9.077) 0.581,11.425 ; -1,9.077 cw(c1.533,9.077) 0.58,11.424 ; -1,9.077 -1,9.077 ; -1,9.077 -1,9.077 ; -1,36.363 ccw(c1.533,36.363) 0.581,34.015 ; -1,36.363 ccw(c1.533,36.363) 0.581,34.015 ; -1,53 cw(c3,53) 2.997,57 ; -1,53 cw(c3,53) 2.997,57 ; -1,53 -1,53 ; 0.58,11.424 cw(c1.533,9.077) 0.584,11.426 ; 0.58,11.425 cw(c0.959,10.499) 0.584,11.426 ; 0.581,11.425 cw(c1.533,9.077) 0.584,11.426 ; 0.581,11.425 cw(c0.959,10.499) 0.584,11.426 ; 0.581,34.015 ccw(c0.959,34.941) 0.584,34.014 ; 0.581,34.015 ccw(c1.533,36.363) 0.584,34.014 ; 0.581,34.015 ccw(c1.533,36.363) 0.584,34.014 ; 0.581,34.015 ccw(c0.959,34.941) 0.584,34.014 ; 0.584,11.426 ccw(c0.384,11.92) 0.917,11.92 ; 0.584,11.426 ccw(c0.384,11.92) 0.917,11.92 ; 0.584,34.014 cw(c0.384,33.52) 0.917,33.52 ; 0.584,34.014 cw(c0.384,33.52) 0.917,33.52 ; 0.917,11.92 cw(c1.917,11.92) 0.917,11.922 ; 0.917,11.92 cw(c1.917,11.92) 0.917,11.922 ; 0.917,11.92 0.917,11.922 ; 0.917,11.92 0.917,11.922 ; 0.917,11.922 0.917,33.518 ; 0.917,11.922 0.917,33.518 ; 0.917,33.518 cw(c1.917,33.52) 0.917,33.52 ; 0.917,33.518 cw(c1.917,33.52) 0.917,33.52 ; 0.917,33.518 0.917,33.52 ; 0.917,33.518 0.917,33.52 ; 2.997,57 cw(c3,53) 3,57 ; 2.997,57 cw(c3,56) 3,57 ; 2.997,57 cw(c3,53) 3,57 ; 2.997,57 cw(c3,56) 3,57 ; 3,-1 3,-1 ; 3,-1 3,-1 ; 3,-1 82,-1 ; 3,-1 3,-1 ; 3,-1 3,-1 ; 3,-1 82,-1 ; 3,57 82.003,57 cw(c82,53) 86,53 ; 82,-1 ccw(c82,3) 86,2.997 ; 82,-1 ccw(c82,3) 86,2.997 ; 82,-1 82,-1 ; 82,-1 82,-1 ; 84.43,27.239 cw(c84.963,27.239) 84.586,27.616 ; 84.43,27.239 84.43,18.559 ccw(c84.963,18.559) 84.586,18.182 85.47,17.298 ; 84.43,27.239 84.43,27.239 ; 84.586,27.616 ccw(c83.879,28.323) 84.587,27.617 ; 84.587,27.617 84.772,27.802 ; 84.586,27.616 84.587,27.617 ; 84.772,27.802 ccw(c84.065,28.509) 84.773,27.803 ; 84.772,27.802 84.773,27.803 ; 84.773,27.803 84.957,27.987 ; 84.957,27.987 ccw(c84.251,28.695) 84.958,27.988 ; 84.957,27.987 84.958,27.988 ; 84.958,27.988 ccw(c84.251,28.695) 84.958,27.988 ; 84.958,27.988 85.47,28.5 ccw(c84.191,29.779) 86,29.776 ; 85.47,17.298 cw(c84.191,16.019) 85.473,17.296 ; 85.47,17.298 cw(c84.763,16.591) 85.473,17.296 ; 85.473,17.296 cw(c84.191,16.019) 86,16.022 ; 86,2.997 ccw(c82,3) 86,3 ; 86,2.997 ccw(c85,3) 86,3 ; 86,2.997 ccw(c82,3) 86,3 ; 86,2.997 ccw(c85,3) 86,3 ; 86,2.997 86,3 ; 86,16.019 ccw(c85,16.019) 86,16.022 ; 86,16.019 ccw(c83.467,16.019) 86,16.022 ; 86,16.019 ccw(c85,16.019) 86,16.022 ; 86,16.019 ccw(c83.467,16.019) 86,16.022 ; 86,16.019 ccw(c84.191,16.019) 86,16.022 ; 86,16.019 ccw(c85,16.019) 86,16.022 ; 86,16.019 ccw(c83.467,16.019) 86,16.022 ; 86,16.019 ccw(c85,16.019) 86,16.022 ; 86,16.019 ccw(c83.467,16.019) 86,16.022 ; 86,16.019 ccw(c85,16.019) 86,16.022 ; 86,29.729 ccw(c85,29.732) 86,29.732 ; 86,29.729 ccw(c82,29.732) 86,29.732 ; 86,29.729 ccw(c82,29.732) 86,29.732 ; 86,29.729 ccw(c85,29.732) 86,29.732 ; 86,29.729 86,29.732 ; 86,29.729 86,29.732 ; 86,29.732 86,29.832 ; 86,29.732 86,29.832 ; 86,29.776 ccw(c83.467,29.779) 86,29.779 ; 86,29.776 ccw(c85,29.779) 86,29.779 ; 86,29.776 ccw(c85,29.779) 86,29.779 ; 86,29.776 ccw(c83.467,29.779) 86,29.779 ; 86,29.776 ccw(c84.191,29.779) 86,29.779 ; 86,29.776 ccw(c85,29.779) 86,29.779 ; 86,29.776 ccw(c83.467,29.779) 86,29.779 ; 86,29.776 ccw(c85,29.779) 86,29.779 ; 86,29.776 ccw(c85,29.779) 86,29.779 ; 86,29.776 ccw(c83.467,29.779) 86,29.779 ; 86,29.832 86,39.98 ; 86,39.98 86,39.98 ; 86,39.98 86,39.98 ; 86,53 86,53
Board:
  lines w0.1: 82,55.999 cw(c82,52.999) 85,52.999 85,29.779 cw(c84.191,29.779) 84.763,29.207 84.251,28.695 84.065,28.509 83.879,28.323 ccw(c84.963,27.239) 83.43,27.239 83.43,18.559 ccw(c84.963,18.559) 83.879,17.475 84.065,17.289 84.251,17.103 84.763,16.591 cw(c84.191,16.019) 85,16.019 85,3 cw(c82,3) 82,0 3,0 cw(c3,3) 0,3 0,9.077 cw(c1.533,9.077) 0.959,10.499 ccw(c0.384,11.92) 1.917,11.92 1.917,33.52 ccw(c0.384,33.52) 0.959,34.941 cw(c1.533,36.363) 0,36.363 0,53 cw(c3,53) 3,56 82,56 ; 84.696,54.33 cw(c84.696,54.33) 84.696,54.33 ; 0,45.863 0,45.863
Mechanical 41:
  drawing of 3006 lines, arcs and shapes, not listed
